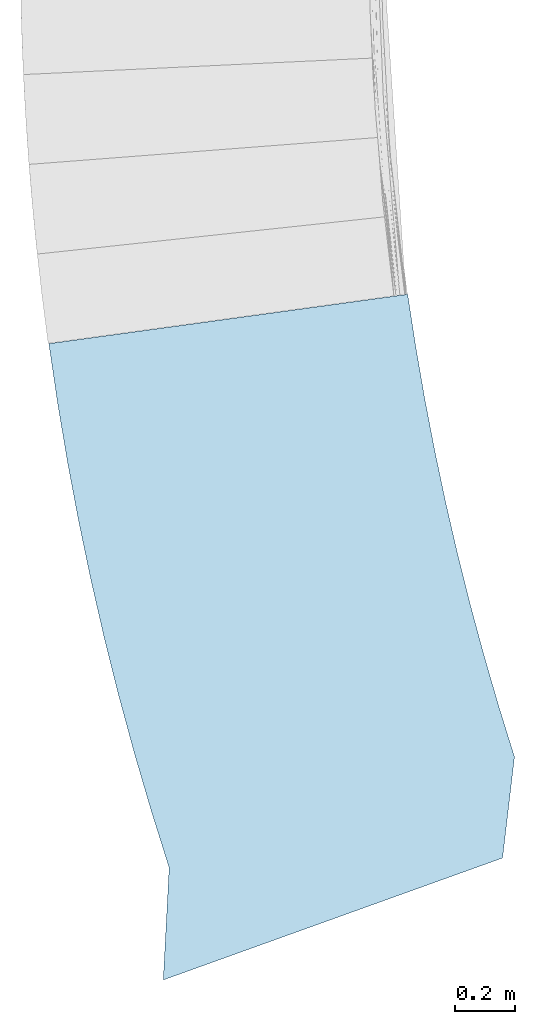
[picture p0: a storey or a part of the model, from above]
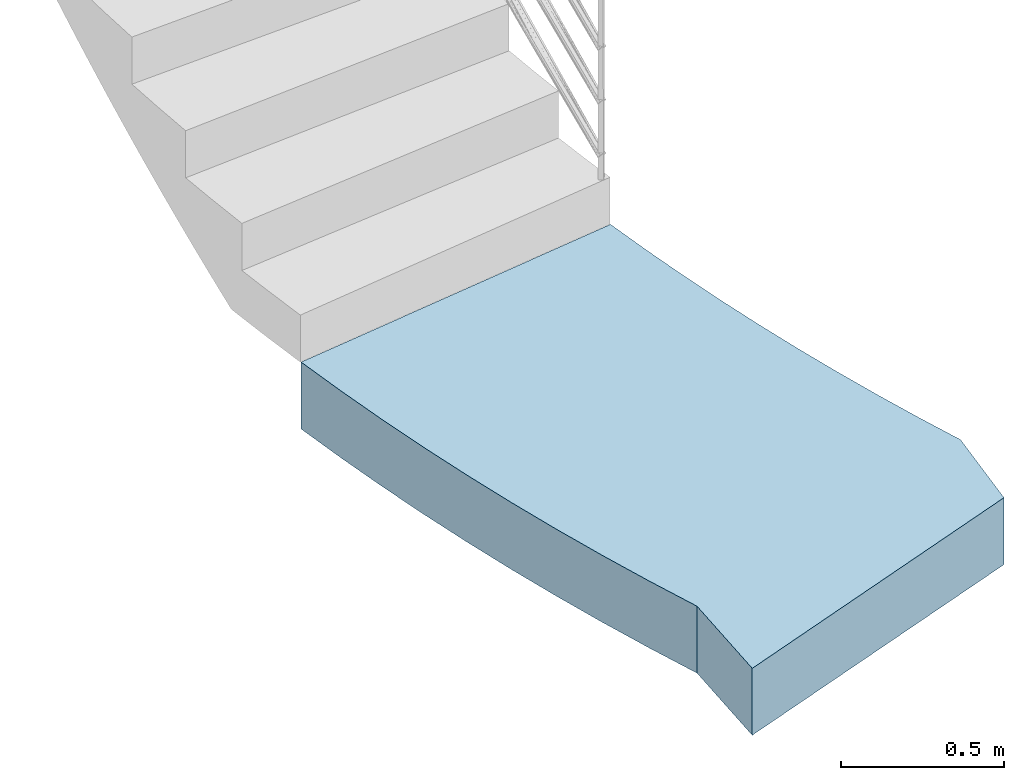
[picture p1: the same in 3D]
Properties of the parts of a building model (IFC2X3)

# File
Description: ViewDefinition [CoordinationView_V2.0]
File name: 0001
Time: 2020-01-28T08:30:23
Written by: The EXPRESS Data Manager Version 5.02.0100.07 : 28 Aug 2013
Made in: 20180328_1600(x64) - Exporter 19.0.1.1 - Interface utilisateur alternative 19.0.1.1
Comment: STEP Physical File produced by: The EXPRESS Data Manager Version 5.02.0100.07 : 28 Aug 2013 * Module: EDMstepFileFactory/EDMstandAlone * Creation date: Tue Jan 28 08:30:23 2020 * Host: DESKTOP-9P9QGN2 * Database: C:\Users\Greta\AppData\Local\Temp\{CF642A6E-FF8D-45D2-BE99-C777C7E1DD9C}\ifc * Database version: 5507 * Database creation date: Tue Jan 28 08:30:13 2020 * Schema: IFC2X3 * Model: DataRepository.ifc * Model creation date: Tue Jan 28 08:30:14 2020 * Header model: DataRepository.ifc_HeaderModel * Header model creation date: Tue Jan 28 08:30:14 2020 * EDMuser: sdai-user * EDMgroup: sdai-group * License ID and type: 5605 : Permanent license. Expiry date: * EDMstepFileFactory options: 020000

# IfcProject, 0001
LongName: FORMATION REVIT; Phase: Etat du projet

# IfcSite, Default
RefLatitude: 47, 22, 11, 900024; RefLongitude: 0, 40, 47, 953891; RefElevation: 4600 cm

# IfcBuilding
Pset_BuildingCommon - NumberOfStoreys: 8

# IfcBuildingStorey (8)
Name | LongName | Elevation (cm)
Niveau Fond de fosse | Niveau Fond de fosse | -984
Niveau haut radier | Niveau haut radier | -870
Pallier intermédiaire | Pallier intermédiaire | -604
Haut escalier | Haut escalier | -340
Niveau dessus pieux | Niveau dessus pieux | -200
Niveau dessus voiles | Niveau dessus voiles | -80
Niveau dessus dalle | Niveau dessus dalle | -50
Niveau TN fini | Niveau TN fini | 0

# IfcBeam: Précoulé-Poutre rectangulaire:400 RB 500 (4)
In: Niveau dessus voiles
Type - PredefinedType: BEAM
Material: Béton - Béton précoulé - 35 MPa
Pset_BeamCommon - LoadBearing: yes; IsExternal: no; Reference: 400 RB 500; Slope: 0 deg
Name (Précoulé-Poutre rectangulaire:400 RB 500:...)
235595
235965
236267
236487

# IfcColumn: 500mm (8)
In: Niveau haut radier
Type - ElementType: 500mm; PredefinedType: COLUMN
Material: Maçonnerie - Béton coulé sur place
Pset_ColumnCommon - LoadBearing: yes; IsExternal: no; Reference: 500mm
Name (Poteau béton - Arrondi:500mm:...)
171862
176105
176589
178975
179308
179356
179388
179419

# IfcFlowSegment: Canalisation:Buse béton EP, Canalisation:Buse béton EP:269941
In: Niveau haut radier
Pset_DistributionFlowElementCommon - Reference: Buse béton EP

# IfcRailing: Garde-corps:Tuyau 900 mm (2)
Pset_RailingCommon - IsExternal: no; Reference: Tuyau 900 mm; Height: 90 cm
Name (Garde-corps:Tuyau 900 mm:...) | In
250194 | Niveau haut radier
251366 | Pallier intermédiaire

# IfcSlab: Pieu béton - JBTP:600mm 2 (134)
In: Niveau Fond de fosse
PredefinedType: BASESLAB; Material: Maçonnerie - Béton coulé sur place
Pset_SlabCommon - Reference: 600mm 2; IsExternal: no
Name (Pieu béton - JBTP:600mm 2:...) | PitchAngle (deg) | Group
155358 | 0 | Groupe de modèles:Groupe de réseaux 1:158767
158770 |  | Groupe de modèles:Groupe de réseaux 1:158772
158780 |  | Groupe de modèles:Groupe de réseaux 1:158782
158796 | 0 | Groupe de modèles:Groupe de réseaux 1:158798
158808 | 0 | Groupe de modèles:Groupe de réseaux 1:158810
158811 | 0 | Groupe de modèles:Groupe de réseaux 1:158813
158814 | 0 | Groupe de modèles:Groupe de réseaux 1:158816
158817 | 0 | Groupe de modèles:Groupe de réseaux 1:158819
158820 | 0 | Groupe de modèles:Groupe de réseaux 1:158822
158823 | 0 | Groupe de modèles:Groupe de réseaux 1:158825
158826 | 0 | Groupe de modèles:Groupe de réseaux 1:158828
158829 | 0 | Groupe de modèles:Groupe de réseaux 1:158831
158832 | 0 | Groupe de modèles:Groupe de réseaux 1:158834
158835 | 0 | Groupe de modèles:Groupe de réseaux 1:158837
158838 | 0 | Groupe de modèles:Groupe de réseaux 1:158840
158841 | 0 | Groupe de modèles:Groupe de réseaux 1:158843
158844 | 0 | Groupe de modèles:Groupe de réseaux 1:158846
158847 | 0 | Groupe de modèles:Groupe de réseaux 1:158849
158850 | 0 | Groupe de modèles:Groupe de réseaux 1:158852
158853 | 0 | Groupe de modèles:Groupe de réseaux 1:158855
158856 | 0 | Groupe de modèles:Groupe de réseaux 1:158858
158859 | 0 | Groupe de modèles:Groupe de réseaux 1:158861
158862 | 0 | Groupe de modèles:Groupe de réseaux 1:158864
158865 | 0 | Groupe de modèles:Groupe de réseaux 1:158867
158868 | 0 | Groupe de modèles:Groupe de réseaux 1:158870
158871 | 0 | Groupe de modèles:Groupe de réseaux 1:158873
158874 | 0 | Groupe de modèles:Groupe de réseaux 1:158876
158877 | 0 | Groupe de modèles:Groupe de réseaux 1:158879
158880 | 0 | Groupe de modèles:Groupe de réseaux 1:158882
158883 | 0 | Groupe de modèles:Groupe de réseaux 1:158885
158886 | 0 | Groupe de modèles:Groupe de réseaux 1:158888
158889 | 0 | Groupe de modèles:Groupe de réseaux 1:158891
158892 | 0 | Groupe de modèles:Groupe de réseaux 1:158894
158895 | 0 | Groupe de modèles:Groupe de réseaux 1:158897
158898 | 0 | Groupe de modèles:Groupe de réseaux 1:158900
158901 | 0 | Groupe de modèles:Groupe de réseaux 1:158903
158904 | 0 | Groupe de modèles:Groupe de réseaux 1:158906
158907 | 0 | Groupe de modèles:Groupe de réseaux 1:158909
158910 | 0 | Groupe de modèles:Groupe de réseaux 1:158912
158913 | 0 | Groupe de modèles:Groupe de réseaux 1:158915
158916 | 0 | Groupe de modèles:Groupe de réseaux 1:158918
158919 | 0 | Groupe de modèles:Groupe de réseaux 1:158921
158922 | 0 | Groupe de modèles:Groupe de réseaux 1:158924
158925 | 0 | Groupe de modèles:Groupe de réseaux 1:158927
158928 | 0 | Groupe de modèles:Groupe de réseaux 1:158930
158931 | 0 | Groupe de modèles:Groupe de réseaux 1:158933
158934 | 0 | Groupe de modèles:Groupe de réseaux 1:158936
158937 | 0 | Groupe de modèles:Groupe de réseaux 1:158939
158940 | 0 | Groupe de modèles:Groupe de réseaux 1:158942
158943 | 0 | Groupe de modèles:Groupe de réseaux 1:158945
158946 | 0 | Groupe de modèles:Groupe de réseaux 1:158948
158949 | 0 | Groupe de modèles:Groupe de réseaux 1:158951
158952 | 0 | Groupe de modèles:Groupe de réseaux 1:158954
158955 | 0 | Groupe de modèles:Groupe de réseaux 1:158957
158958 | 0 | Groupe de modèles:Groupe de réseaux 1:158960
158961 | 0 | Groupe de modèles:Groupe de réseaux 1:158963
158964 | 0 | Groupe de modèles:Groupe de réseaux 1:158966
158967 | 0 | Groupe de modèles:Groupe de réseaux 1:158969
158970 | 0 | Groupe de modèles:Groupe de réseaux 1:158972
158973 | 0 | Groupe de modèles:Groupe de réseaux 1:158975
158976 | 0 | Groupe de modèles:Groupe de réseaux 1:158978
158979 | 0 | Groupe de modèles:Groupe de réseaux 1:158981
158982 | 0 | Groupe de modèles:Groupe de réseaux 1:158984
158985 | 0 | Groupe de modèles:Groupe de réseaux 1:158987
158988 | 0 | Groupe de modèles:Groupe de réseaux 1:158990
158991 | 0 | Groupe de modèles:Groupe de réseaux 1:158993
158994 | 0 | Groupe de modèles:Groupe de réseaux 1:158996
158997 | 0 | Groupe de modèles:Groupe de réseaux 1:158999
159000 | 0 | Groupe de modèles:Groupe de réseaux 1:159002
159003 | 0 | Groupe de modèles:Groupe de réseaux 1:159005
159006 | 0 | Groupe de modèles:Groupe de réseaux 1:159008
159009 | 0 | Groupe de modèles:Groupe de réseaux 1:159011
159012 | 0 | Groupe de modèles:Groupe de réseaux 1:159014
159015 | 0 | Groupe de modèles:Groupe de réseaux 1:159017
159018 | 0 | Groupe de modèles:Groupe de réseaux 1:159020
159021 | 0 | Groupe de modèles:Groupe de réseaux 1:159023
159024 | 0 | Groupe de modèles:Groupe de réseaux 1:159026
159027 | 0 | Groupe de modèles:Groupe de réseaux 1:159029
159030 | 0 | Groupe de modèles:Groupe de réseaux 1:159032
159033 | 0 | Groupe de modèles:Groupe de réseaux 1:159035
159036 | 0 | Groupe de modèles:Groupe de réseaux 1:159038
159039 | 0 | Groupe de modèles:Groupe de réseaux 1:159041
159042 | 0 | Groupe de modèles:Groupe de réseaux 1:159044
159045 | 0 | Groupe de modèles:Groupe de réseaux 1:159047
159048 | 0 | Groupe de modèles:Groupe de réseaux 1:159050
159051 | 0 | Groupe de modèles:Groupe de réseaux 1:159053
159054 | 0 | Groupe de modèles:Groupe de réseaux 1:159056
159057 | 0 | Groupe de modèles:Groupe de réseaux 1:159059
159060 | 0 | Groupe de modèles:Groupe de réseaux 1:159062
159063 | 0 | Groupe de modèles:Groupe de réseaux 1:159065
159066 | 0 | Groupe de modèles:Groupe de réseaux 1:159068
159069 | 0 | Groupe de modèles:Groupe de réseaux 1:159071
159072 | 0 | Groupe de modèles:Groupe de réseaux 1:159074
159075 | 0 | Groupe de modèles:Groupe de réseaux 1:159077
159078 | 0 | Groupe de modèles:Groupe de réseaux 1:159080
159081 | 0 | Groupe de modèles:Groupe de réseaux 1:159083
159084 | 0 | Groupe de modèles:Groupe de réseaux 1:159086
159087 | 0 | Groupe de modèles:Groupe de réseaux 1:159089
159090 | 0 | Groupe de modèles:Groupe de réseaux 1:159092
159093 | 0 | Groupe de modèles:Groupe de réseaux 1:159095
159096 | 0 | Groupe de modèles:Groupe de réseaux 1:159098
159099 | 0 | Groupe de modèles:Groupe de réseaux 1:159101
159102 | 0 | Groupe de modèles:Groupe de réseaux 1:159104
159105 | 0 | Groupe de modèles:Groupe de réseaux 1:159107
159108 | 0 | Groupe de modèles:Groupe de réseaux 1:159110
159111 | 0 | Groupe de modèles:Groupe de réseaux 1:159113
159114 | 0 | Groupe de modèles:Groupe de réseaux 1:159116
159117 | 0 | Groupe de modèles:Groupe de réseaux 1:159119
159120 | 0 | Groupe de modèles:Groupe de réseaux 1:159122
159123 | 0 | Groupe de modèles:Groupe de réseaux 1:159125
159126 | 0 | Groupe de modèles:Groupe de réseaux 1:159128
159129 | 0 | Groupe de modèles:Groupe de réseaux 1:159131
159132 | 0 | Groupe de modèles:Groupe de réseaux 1:159134
159135 | 0 | Groupe de modèles:Groupe de réseaux 1:159137
159138 | 0 | Groupe de modèles:Groupe de réseaux 1:159140
159141 | 0 | Groupe de modèles:Groupe de réseaux 1:159143
159144 | 0 | Groupe de modèles:Groupe de réseaux 1:159146
159147 | 0 | Groupe de modèles:Groupe de réseaux 1:159149
159150 | 0 | Groupe de modèles:Groupe de réseaux 1:159152
159153 | 0 | Groupe de modèles:Groupe de réseaux 1:159155
159156 | 0 | Groupe de modèles:Groupe de réseaux 1:159158
159159 | 0 | Groupe de modèles:Groupe de réseaux 1:159161
159162 | 0 | Groupe de modèles:Groupe de réseaux 1:159164
159165 | 0 | Groupe de modèles:Groupe de réseaux 1:159167
159168 | 0 | Groupe de modèles:Groupe de réseaux 1:159170
159171 | 0 | Groupe de modèles:Groupe de réseaux 1:159173
159174 | 0 | Groupe de modèles:Groupe de réseaux 1:159176
159177 | 0 | Groupe de modèles:Groupe de réseaux 1:159179
159180 | 0 | Groupe de modèles:Groupe de réseaux 1:159182
159183 | 0 | Groupe de modèles:Groupe de réseaux 1:159185
159186 | 0 | Groupe de modèles:Groupe de réseaux 1:159188
159189 | 0 | Groupe de modèles:Groupe de réseaux 1:159191
159192 | 0 | Groupe de modèles:Groupe de réseaux 1:159194
159195 | 0 | Groupe de modèles:Groupe de réseaux 1:159197

# IfcSlab: Radier:Radier 400mm - JBTP, Radier:Radier 400mm - JBTP:159334
In: Niveau Fond de fosse
PredefinedType: BASESLAB; Material: Béton, coulé sur place 40 cm
Pset_SlabCommon - LoadBearing: yes; IsExternal: no; PitchAngle: 0 deg; Reference: Radier 400mm - JBTP; ThermalTransmittance: 2.615 kg/K/s3

# IfcSlab: Sol:Béton - 250mm JBTP (4)
PredefinedType: FLOOR; Material: Béton, coulé sur place 25 cm
Pset_SlabCommon - LoadBearing: yes; IsExternal: no; PitchAngle: 0 deg; Reference: Béton - 250mm JBTP; ThermalTransmittance: 4.184 kg/K/s3
Name (Sol:Béton - 250mm JBTP:...) | In
165710 | Niveau dessus pieux
252249 | Pallier intermédiaire
252775 | Haut escalier
270723 | Niveau TN fini

# IfcSlab: Sol:Béton - 400mm JBTP (4)
PredefinedType: FLOOR
Pset_SlabCommon - LoadBearing: yes; IsExternal: no; Reference: Béton - 400mm JBTP; ThermalTransmittance: 2.615 kg/K/s3
Name (Sol:Béton - 400mm JBTP:...) | In | Material
162973 | Niveau haut radier | Béton, coulé sur place
163478 | Niveau haut radier | Béton, coulé sur place 40 cm
240923 | Niveau dessus dalle | Béton, coulé sur place 40 cm
270144 | Niveau haut radier | Béton, coulé sur place 40 cm | Pset_SlabCommon - PitchAngle: 0 deg

# IfcSlab: Sol:Générique 300 mm, Sol:Générique 300 mm:171598
In: Niveau TN fini
PredefinedType: FLOOR; Material: Sol par défaut 30 cm
Pset_SlabCommon - LoadBearing: yes; IsExternal: no; Reference: Générique 300 mm

# IfcStair: Escalier préfabriqué:Escalier préfabriqué:93332 (2)
Pset_StairCommon - IsExternal: no; Reference: Escalier préfabriqué; NumberOfRiser: 14; NumberOfTreads: 13; TreadLength: 25 cm
Name (Escalier préfabriqué:Escalier:...) | In | RiserHeight (cm)
248836 | Niveau haut radier | 19
251086 | Pallier intermédiaire | 17.6

# IfcStairFlight: Escalier préfabriqué:Escalier préfabriqué:93332 (2)
NumberOfRiser: 14; NumberOfTreads: 13; TreadLength: 0.82021 cm; Material: Béton, coulé sur place
Pset_StairFlightCommon - Reference: Profondeur de structure 170 mm; NumberOfRiser: 14; NumberOfTreads: 13; TreadLength: 25 cm; TreadLengthAtOffset: 25 cm; NosingLength: 0 cm
Name (Escalier préfabriqué:Escalier:...) | In | RiserHeight (cm) | Pset_StairFlightCommon, RiserHeight (cm)
248836 Run 1 | Niveau haut radier | 0.62336 | 19
251086 Run 1 | Pallier intermédiaire | 0.577428 | 17.6

# IfcWall: Mur de base:Générique - 350 mm 2 (2)
In: Niveau haut radier
Type - Material: Mur par défaut 35 cm
Pset_WallCommon - Reference: Générique - 350 mm 2; LoadBearing: yes; ExtendToStructure: no; IsExternal: yes
Name (Mur de base:Générique - 350 mm 2:...)
140876 | Material: Mur par défaut
140904

# IfcWall: Mur de base:Voile béton ep. 25cm, Mur de base:Voile béton ep. 25cm:164078
In: Niveau haut radier
Type - Material: Mur par défaut 25 cm
Material: Mur par défaut
Pset_WallCommon - LoadBearing: yes; ExtendToStructure: no; IsExternal: yes; Reference: Voile béton ep. 25cm

# IfcWallStandardCase: Mur de base:Générique - 350 mm 2 (2)
In: Niveau haut radier
Type - Material: Mur par défaut 35 cm
Pset_WallCommon - Reference: Générique - 350 mm 2; LoadBearing: yes; ExtendToStructure: no; IsExternal: yes
Name (Mur de base:Générique - 350 mm 2:...)
169641
170955

# IfcWallStandardCase: Mur de base:Voile béton ep. 15cm (20)
Type - PredefinedType: STANDARD; Material: Mur par défaut 20 cm
Pset_WallCommon - LoadBearing: yes; IsExternal: yes; Reference: Voile béton ep. 15cm
Name (Mur de base:Voile béton ep. 15cm:...) | In | ExtendToStructure
244166 | Niveau dessus dalle | no
244170 | Niveau dessus dalle | no
244172 | Niveau dessus dalle | no
244222 | Niveau dessus dalle | no
244226 | Niveau dessus dalle | no
244228 | Niveau dessus dalle | no
244278 | Niveau dessus dalle | no
244280 | Niveau dessus dalle | no
244282 | Niveau dessus dalle | no
244284 | Niveau dessus dalle | no
244324 | Niveau dessus dalle | no
244326 | Niveau dessus dalle | no
244328 | Niveau dessus dalle | no
244330 | Niveau dessus dalle | no
244394 | Niveau dessus dalle | no
244444 | Niveau dessus dalle | no
244516 | Niveau dessus dalle | no
244722 | Niveau dessus dalle | no
270282 | Niveau haut radier | yes
270284 | Niveau haut radier | yes

# IfcWallStandardCase: Mur de base:Voile béton ep. 25cm (5)
Type - Material: Mur par défaut 25 cm
Pset_WallCommon - LoadBearing: yes; ExtendToStructure: no; IsExternal: yes; Reference: Voile béton ep. 25cm
Name (Mur de base:Voile béton ep. 25cm:...) | In
164111 | Niveau Fond de fosse
165787 | Niveau dessus pieux
165789 | Niveau dessus pieux
165791 | Niveau dessus pieux
165793 | Niveau dessus pieux

# IfcWallStandardCase: Mur de base:Voile béton ep. 30cm (12)
In: Niveau Fond de fosse
Type - PredefinedType: STANDARD; Material: Mur par défaut 30 cm
Pset_WallCommon - LoadBearing: yes; IsExternal: yes; Reference: Voile béton ep. 30cm
Name (Mur de base:Voile béton ep. 30cm:...) | ExtendToStructure
160696 | no
160762 | no
160850 | no
160965 | no
161369 | no
161371 | no
161373 | no
161375 | yes
161384 | no
161386 | no
161388 | no
161390 | no
